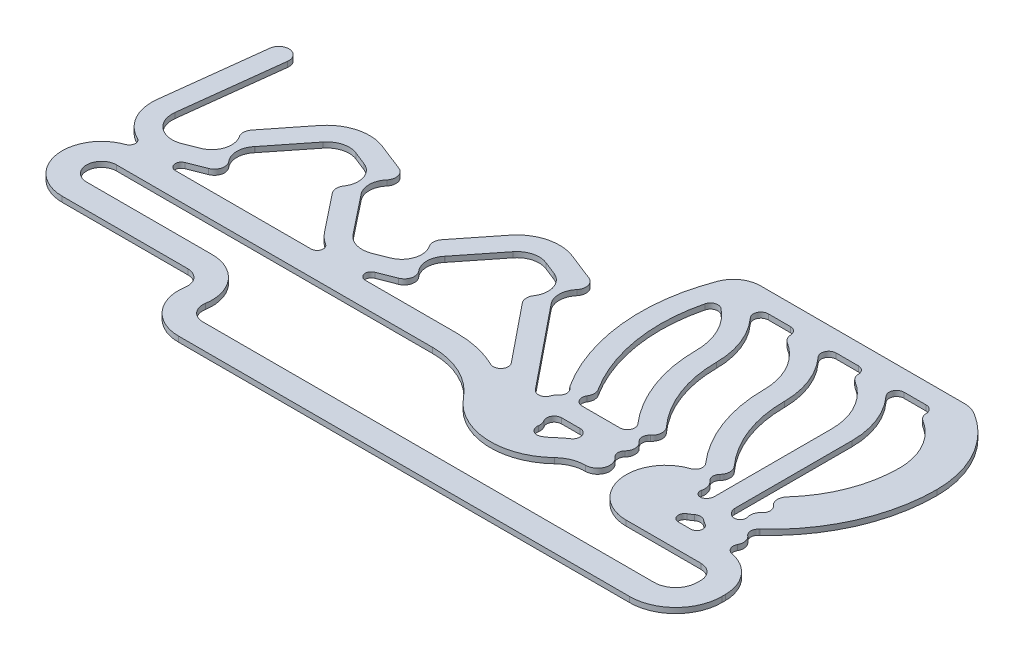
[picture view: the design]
SolidWorks part; units mm, degrees
other "<6021_lower_plate>-<Fillet8>"
ref_plane "X_Y" through (0, 0, 0) normal (0, 0, 1) x (1, 0, 0)
ref_plane "Z_X" through (0, 0, 0) normal (0, 1, 0) x (1, 0, 0)
ref_plane "Y_Z" through (0, 0, 0) normal (1, 0, 0) x (0, 0, -1)
ref_plane "X_Y-6021_lower_plate" through (0, 0, 0) normal (0, 0, 1) x (1, 0, 0)
ref_plane "Z_X-6021_lower_plate" through (0, 0, 0) normal (0, 1, 0) x (1, 0, 0)
ref_plane "Y_Z-6021_lower_plate" through (0, 0, 0) normal (1, 0, 0) x (0, 0, -1)
ref_plane "X_Y-_6021_master-6021_lower_plate" through (0, 0, 0) normal (0, 0, 1) x (1, 0, 0)
ref_plane "Z_X_peltier-_6021_master-6021_lower_plate" through (0, 0, 0) normal (0, 1, 0) x (1, 0, 0)
ref_plane "Y_Z-_6021_master-6021_lower_plate" through (0, 0, 0) normal (1, 0, 0) x (0, 0, -1)
sketch "zx_sketch-_6021_master-6021_lower_plate" plane through (0, 0, 0) normal (0, 1, 0) x (1, 0, 0)
  line L0 (0, 0) -> (0, 39833.2138) construction
  line L1 (-56.5, 24.66) -> (4, 24.66)
  line L2 (-56.5, 24.66) -> (-56.5, -27)
  line L3 (-56.5, -27) -> (56.5, -27)
  line L4 (56.5, 27) -> (56.5, -27)
  line L5 (0, 0) -> (39833.2138, 0) construction
  line L6 (4, 24.66) -> (4, 27)
  line L11 (4, 27) -> (56.5, 27)
  point P3 (0, -27)
  point P17 (-22.5, 15.66)
  point P18 (22.5, 15.66)
  point P19 (22.5, -15.66)
  point P20 (-22.5, -15.66)
  dimension "D1" = 113
  dimension "D2" = 24.66
  dimension "D3" = 45
  dimension "D4" = 31.32
  dimension "D5" = 27
  dimension "D6" = 2.34
  dimension "D7" = 4
  dimension "D8" = 27
sketch "xy_sketch-_6021_master-6021_lower_plate" plane through (0, 0, 0) normal (0, 0, 1) x (1, 0, 0)
  line L0 (0, 0) -> (0, 5) construction
  line L1 (0, 5) -> (0, 10) construction
  dimension "D1" = 5
  dimension "D2" = 5
ref_plane "zx_lower_plate-_6021_master-6021_lower_plate" through (0, 5, 0) normal (0, 1, 0) x (1, 0, 0)
ref_plane "zx_sensor-_6021_master-6021_lower_plate" through (0, 10, 0) normal (0, 1, 0) x (1, 0, 0)
sketch "zx_sensor_sketch-_6021_master-6021_lower_plate" plane through (0, 10, 0) normal (0, 1, 0) x (1, 0, 0)
  line L0 (-42.2, 3.16) -> (-28.2, 8.66) construction
  line L1 (-28.2, 8.66) -> (-14.2, 3.16) construction
  line L2 (-14.2, 3.16) -> (-0.2, 8.66) construction
  line L3 (-42.2, 4.96) -> (-42.2, -0.8) construction
  line L4 (-28.2, 10.46) -> (-28.2, 4.7) construction
  line L5 (-14.2, 4.96) -> (-14.2, -0.8) construction
  line L6 (-0.2, 10.46) -> (-0.2, 4.7) construction
  line L7 (-42.2, 3.16) -> (-42.2, -0.8) construction
  line L8 (-28.2, 8.66) -> (-28.2, 4.7) construction
  line L9 (-14.2, 3.16) -> (-14.2, -0.8) construction
  line L10 (-0.2, 8.66) -> (-0.2, 4.7) construction
  line L11 (-39.215, 3.16) -> (-45.185, 3.16) construction
  line L12 (-39.215, 7.475) -> (-39.215, -1.155) construction
  line L13 (-44.615, 3.16) -> (-39.785, 3.16) construction
  point P8 (-42.2, 2.08)
  point P16 (-42.2, 3.16)
  point P19 (-39.215, 3.16)
  point P22 (-42.2, 3.16)
  dimension "D1" = 42.2
  dimension "D2" = 3.16
  dimension "D3" = 14
  dimension "D4" = 1.08
  dimension "D5" = 3.96
  dimension "D6" = 5.76
  dimension "D7" = 5.97
  dimension "D8" = 0.8
  dimension "D9" = 8.63
  dimension "D10" = 4.83
  dimension "D11" = 5.5
sketch "zx_valve_sketch-_6021_master-6021_lower_plate" plane through (0, 10.9, 0) normal (0, 1, 0) x (1, 0, 0)
  line L0 (44, -4.25) -> (34, -4.25) construction
  line L1 (34, -4.25) -> (24, -4.25) construction
  line L2 (24, -4.25) -> (14, -4.25) construction
  line L3 (44, -10.5) -> (44, -6.5) construction
  line L4 (44, -6.5) -> (44, -2.5) construction
  line L5 (34, -2.5) -> (34, -6.5) construction
  line L6 (34, -6.5) -> (34, -10.5) construction
  line L7 (24, -2.5) -> (24, -6.5) construction
  line L8 (24, -6.5) -> (24, -10.5) construction
  line L9 (14, -2.5) -> (14, -6.5) construction
  line L10 (14, -6.5) -> (14, -10.5) construction
  line L11 (44, 10.5) -> (44, -19) construction
  line L12 (34, 10.5) -> (34, -19) construction
  line L14 (24, -19) -> (24, 10.5) construction
  line L17 (14, 10.5) -> (14, -19) construction
  point P20 (44, -4.25)
  dimension "D1" = 10
  dimension "D2" = 44
  dimension "D3" = 4.25
  dimension "D4" = 8
  dimension "D5" = 2.25
  dimension "D6" = 29.5
  dimension "D7" = 14.2
  dimension "D8" = 10.5
  dimension "D9" = 29.32
sketch "zx_manifold_sketch-_6021_master-6021_lower_plate" plane through (0, 5, 0) normal (0, 1, 0) x (1, 0, 0)
  line L0 (-34.0003, 7.58) -> (-22.3997, 7.58) construction
  line L4 (44, 19.5) -> (34, 19.5) construction
  line L5 (34, 19.5) -> (24, 19.5) construction
  line L6 (24, 19.5) -> (14, 19.5) construction
  line L7 (39, 10.5) -> (39, -7.6132)
  line L9 (-48.0003, 2.08) -> (-36.3997, 2.08) construction
  line L11 (-20.0003, 2.08) -> (-8.3997, 2.08) construction
  line L12 (-6.0003, 7.58) -> (5.6003, 7.58) construction
  line L13 (-48.9, -6.72) -> (-2.2958, -6.72)
  line L15 (14, -6.5) -> (24, -6.5)
  line L17 (-14.2, 4.96) -> (-9.7626, 10.5608)
  line L22 (34, -4.7265) -> (44, -4.7265) construction
  line L23 (44, -4.7265) -> (39, -7.6132) construction
  line L24 (-4.2467, 12.0482) -> (-0.2, 10.46)
  line L26 (44, 22) -> (14, 22)
  line L28 (-48.9, -14.72) -> (-30.3969, -14.72)
  line L30 (10.8896, -9.015) -> (7.7791, -11.53) construction
  line L31 (34, -14.5) -> (45, -14.5)
  line L32 (-22.5, -24) -> (44, -24)
  line L35 (-14.2, -0.8) -> (-18.2467, -2.3882)
  line L38 (-52.7667, 2.6469) -> (-51, 17.5)
  line L39 (-28.2, 4.7) -> (-23.7626, -0.9008)
  line L40 (14, 10.5) -> (22.5, 15.66) construction
  line L43 (49, -19) -> (49, -18.5)
  line L45 (-32.2467, 12.0482) -> (-28.2, 10.46)
  line L46 (-37.7626, 10.5608) -> (-42.2, 4.96)
  line L47 (-42.2, -0.8) -> (-46.2467, -2.3882)
  line L48 (-0.2, 4.7) -> (10.8896, -9.015)
  circle A0 centre (34, 19.5) radius 3.85 construction
  circle A1 centre (44, 19.5) radius 3.85 construction
  circle A2 centre (24, 19.5) radius 3.85 construction
  circle A3 centre (14, 19.5) radius 3.85 construction
  arc A4 (34, -10.5) -> (39, -7.6132) centre (34, -4.7265) ccw
  arc A6 (29, 10.5) -> (34, -2.5) centre (48.4, 10.5) ccw
  arc A7 (44, -10.5) -> (39, -7.6132) centre (44, -4.7265) cw
  arc A8 (44, -2.5) -> (49, 10.5) centre (29.6, 10.5) ccw
  arc A11 (45.3208, 21.6226) -> (44, 22) centre (44, 19.5) ccw
  arc A12 (44, -6.5) -> (51.5, 10.5) centre (28.4833, 10.5) ccw
  arc A13 (14, 22) -> (11.6636, 20.3896) centre (14, 19.5) ccw
  arc A15 (34, -14.5) -> (34, -6.5) centre (34, -10.5) cw
  arc A16 (-48.9, -6.72) -> (-48.9, -14.72) centre (-48.9, -10.72) ccw
  arc A17 (44, -24) -> (49, -19) centre (44, -19) ccw
  arc A18 (-22.5, -24) -> (-26.4485, -19.36) centre (-22.5, -20) cw
  arc A19 (-30.3969, -14.72) -> (-26.4485, -19.36) centre (-30.3969, -18.72) cw
  arc A20 (14, -10.5) -> (10.8896, -9.015) centre (14, -6.5) cw
  arc A21 (-4.2467, 12.0482) -> (-9.7626, 10.5608) centre (-6.0003, 7.58) ccw
  circle A22 centre (-51, 17.5) radius 3.85 construction
  arc A23 (-23.7626, -0.9008) -> (-18.2467, -2.3882) centre (-20.0003, 2.08) ccw
  arc A24 (-32.2467, 12.0482) -> (-37.7626, 10.5608) centre (-34.0003, 7.58) ccw
  arc A25 (-46.2467, -2.3882) -> (-52.7667, 2.6469) centre (-48.0003, 2.08) cw
  arc A26 (49, -18.5) -> (45, -14.5) centre (45, -18.5) ccw
  circle A27 centre (-51, 17.5) radius 5.5 construction
  arc A29 (14, 19.5) -> (19, 10.5) centre (8.4, 10.5) cw
  arc A30 (39, 10.5) -> (34, 19.5) centre (28.4, 10.5) ccw
  arc A31 (49, 10.5) -> (44, 19.5) centre (38.4, 10.5) ccw
  arc A32 (29, 10.5) -> (24, 19.5) centre (18.4, 10.5) ccw
  arc A33 (19, 10.5) -> (24, -2.5) centre (38.4, 10.5) ccw
  arc A35 (45.3208, 21.6226) -> (51.5, 10.5) centre (38.4, 10.5) cw
  arc A36 (14, -2.5) -> (11.6636, 20.3896) centre (35.6147, 11.2703) cw
  arc A37 (19.5172, -12.2931) -> (7.7791, -11.53) centre (14, -6.5) cw
  arc A38 (7.7791, -11.53) -> (-2.2958, -6.72) centre (-2.2958, -19.6763) ccw
  arc A39 (24, -10.5) -> (19.5172, -12.2931) centre (24, -17) ccw
  point P121 (-42.2, 2.08)
  dimension "D1" = 45.993
  dimension "D2" = 7.2783
  dimension "D4" = 85.419
  dimension "D5" = 58.011
  dimension "D6" = 92.9
  dimension "D7" = 34.592
  dimension "D8" = 47.712
  dimension "D9" = 60.268
  dimension "D10" = 5
  dimension "D13" = 34.946
  dimension "D14" = 17.5
  dimension "D15" = 15.65
  dimension "D16" = 70.41
  dimension "D17" = 173.817
  dimension "D19" = 30.895
  dimension "D21" = 0.7861
  dimension "D18" = 47.65
  dimension "D11" = 26.15
  dimension "D3" = 9
  dimension "D12" = 3
  dimension "D20" = 3.485
sketch "zx_screws_sketch-_6021_master-6021_lower_plate" plane through (0, 5, 0) normal (0, 1, 0) x (1, 0, 0)
  line L4 (-34.0003, 7.58) -> (-22.3997, 7.58) construction
  line L5 (-20.0003, 2.08) -> (-8.3997, 2.08) construction
  line L6 (-6.0003, 7.58) -> (5.6003, 7.58) construction
  line L7 (-36.3997, 2.08) -> (-48.0003, 2.08) construction
  line L13 (56.5, 27) -> (56.5, -27) construction
  circle A0 centre (52.5, 23) radius 4 construction
  circle A3 centre (52.5, -23) radius 4 construction
  arc A7 (-52.7667, 2.6469) -> (-46.2467, -2.3882) centre (-48.0003, 2.08) ccw construction
  circle A8 centre (-52.5, -23) radius 4 construction
  point P0 (-0.2, -19)
  point P1 (52.5, -23)
  point P2 (52.5, 23)
  point P3 (6.6, 23)
  point P4 (-52.5, -23)
  point P5 (-42.2, 17.5)
  dimension "D3" = 5.743
  dimension "D4" = 4.3941
  dimension "D11" = 7.7312
  dimension "D1" = 44.8364
  dimension "D2" = 4
  dimension "D5" = 3.6997
  dimension "D6" = 15
  dimension "D7" = 6.6
  dimension "D8" = 52.5
  dimension "D9" = 57.717
  dimension "D10" = 4
ref_plane "yz_sensor-_6021_master-6021_lower_plate" through (-42.2, 0, 0) normal (1, 0, 0) x (0, 0, -1)
ref_plane "zx_valve-_6021_master-6021_lower_plate" through (0, 10.9, 0) normal (0, 1, 0) x (1, 0, 0)
ref_plane "zx_sensor_shelf-_6021_master-6021_lower_plate" through (0, 12.391, 0) normal (0, 1, 0) x (1, 0, 0)
sketch "Sketch7-6021_lower_plate" plane through (0, 5, 0) normal (0, 1, 0) x (1, 0, 0)
  line L6 (-56.5, -27) -> (56.5, -27)
  line L7 (56.5, 27) -> (56.5, -27)
  line L8 (4, 27) -> (56.5, 27)
  line L9 (4, 24.66) -> (4, 27)
  line L10 (-56.5, 24.66) -> (4, 24.66)
  line L11 (-56.5, 24.66) -> (-56.5, -27)
sketch "Sketch33-6021_lower_plate" plane through (0, 5, 0) normal (0, 1, 0) x (1, 0, 0)
  line L6 (-50.6814, 2.3989) -> (-48.9147, 17.252)
  line L7 (-42.9672, 1.1548) -> (-47.0139, -0.4334)
  line L10 (-54.852, 2.895) -> (-53.0853, 17.748)
  line L11 (-41.4328, -2.7548) -> (-45.4795, -4.343)
  line L15 (44, 24.1) -> (14, 24.1)
  line L19 (44, 19.9) -> (14, 19.9)
  line L23 (-40.554, 3.6559) -> (-36.1166, 9.2567)
  line L24 (-33.0139, 10.0934) -> (-28.9672, 8.5052)
  line L27 (-43.846, 6.2641) -> (-39.4086, 11.8649)
  line L28 (-31.4795, 14.003) -> (-27.4328, 12.4148)
  line L33 (-17.4795, -4.343) -> (-13.4328, -2.7548)
  line L34 (-29.846, 3.3959) -> (-25.4086, -2.2049)
  line L37 (-19.0139, -0.4334) -> (-14.9672, 1.1548)
  line L38 (-26.554, 6.0041) -> (-22.1166, 0.4033)
  line L40 (-1.833, 3.3796) -> (9.2566, -10.3354)
  line L43 (-5.0139, 10.0934) -> (-0.9672, 8.5052)
  line L44 (-12.554, 3.6559) -> (-8.1166, 9.2567)
  line L47 (-3.4795, 14.003) -> (0.5672, 12.4148)
  line L48 (-15.846, 6.2641) -> (-11.4086, 11.8649)
  line L50 (1.433, 6.0204) -> (12.5225, -7.6946)
  arc A0 (-53.0853, 17.748) -> (-48.9147, 17.252) centre (-51, 17.5) cw
  arc A1 (-42.9672, 1.1548) -> (-41.4328, -2.7548) centre (-42.2, -0.8) cw
  arc A3 (-50.6814, 2.3989) -> (-47.0139, -0.4334) centre (-48.0003, 2.08) ccw
  arc A5 (-54.852, 2.895) -> (-45.4795, -4.343) centre (-48.0003, 2.08) ccw
  arc A9 (-1.833, 3.3796) -> (1.433, 6.0204) centre (-0.2, 4.7) cw
  arc A14 (-33.0139, 10.0934) -> (-36.1166, 9.2567) centre (-34.0003, 7.58) ccw
  arc A16 (-31.4795, 14.003) -> (-39.4086, 11.8649) centre (-34.0003, 7.58) ccw
  arc A32 (12.2289, -3.6283) -> (15.7711, -1.3717) centre (14, -2.5) ccw
  arc A33 (14, -8.4) -> (14, -12.6) centre (14, -10.5) cw
  arc A34 (42.5843, -4.949) -> (45.4157, -8.051) centre (44, -6.5) ccw
  arc A43 (-25.4086, -2.2049) -> (-17.4795, -4.343) centre (-20.0003, 2.08) ccw
  arc A45 (-22.1166, 0.4033) -> (-19.0139, -0.4334) centre (-20.0003, 2.08) ccw
  arc A48 (-5.0139, 10.0934) -> (-8.1166, 9.2567) centre (-6.0003, 7.58) ccw
  arc A50 (-3.4795, 14.003) -> (-11.4086, 11.8649) centre (-6.0003, 7.58) ccw
  arc A51 (-43.846, 6.2641) -> (-40.554, 3.6559) centre (-42.2, 4.96) ccw
  arc A56 (-28.9672, 8.5052) -> (-27.4328, 12.4148) centre (-28.2, 10.46) ccw
  arc A57 (-29.846, 3.3959) -> (-26.554, 6.0041) centre (-28.2, 4.7) cw
  arc A58 (-15.846, 6.2641) -> (-12.554, 3.6559) centre (-14.2, 4.96) ccw
  arc A59 (-14.9672, 1.1548) -> (-13.4328, -2.7548) centre (-14.2, -0.8) cw
  arc A60 (0.5672, 12.4148) -> (-0.9672, 8.5052) centre (-0.2, 10.46) cw
  arc A67 (9.7011, 21.1368) -> (12.2289, -3.6283) centre (35.6147, 11.2703) ccw
  arc A69 (9.2566, -10.3354) -> (14, -12.6) centre (14, -6.5) ccw
  arc A71 (12.5225, -7.6946) -> (14, -8.4) centre (14, -6.5) ccw
  arc A72 (14, 24.1) -> (9.7011, 21.1368) centre (14, 19.5) ccw
  arc A73 (46.4302, 23.4057) -> (44, 24.1) centre (44, 19.5) ccw
  arc A74 (53.6, 10.5) -> (46.4302, 23.4057) centre (38.4, 10.5) ccw
  arc A75 (45.4157, -8.051) -> (53.6, 10.5) centre (28.4833, 10.5) ccw
  arc A81 (13.6262, 19.6423) -> (15.7711, -1.3717) centre (35.6147, 11.2703) ccw
  arc A82 (14, 19.9) -> (13.6262, 19.6423) centre (14, 19.5) ccw
  arc A83 (44.2113, 19.8396) -> (44, 19.9) centre (44, 19.5) ccw
  arc A84 (49.4, 10.5) -> (44.2113, 19.8396) centre (38.4, 10.5) ccw
  arc A85 (42.5843, -4.949) -> (49.4, 10.5) centre (28.4833, 10.5) ccw
  dimension "D5" = 2.1
  dimension "D13" = 2.1
  dimension "D11" = 2.1
  dimension "D3" = 2.1
  dimension "D1" = 2.1
  dimension "D2" = 2.1
  dimension "D4" = 2.1
  dimension "D6" = 2.1
  dimension "D7" = 2.1
  dimension "D8" = 2.1
  dimension "D9" = 2.1
  dimension "D10" = 2.1
  dimension "D12" = 2.1
  dimension "D14" = 2.1
sketch "Sketch34-6021_lower_plate" plane through (0, 5, 0) normal (0, 1, 0) x (1, 0, 0)
  line L5 (41.1, -6.9814) -> (41.1, 10.5)
  line L7 (36.9, -6.9814) -> (36.9, 10.5)
  line L10 (14, -8.6) -> (24, -8.6)
  line L12 (14, -4.4) -> (24, -4.4)
  arc A5 (14, -4.4) -> (14, -8.6) centre (14, -6.5) ccw
  arc A11 (31.1, 10.5) -> (35.5588, -1.0928) centre (48.4, 10.5) ccw
  arc A12 (31.1, 10.5) -> (25.1094, 21.283) centre (18.4, 10.5) ccw
  arc A15 (26.9, 10.5) -> (32.4412, -3.9072) centre (48.4, 10.5) ccw
  arc A16 (26.9, 10.5) -> (22.8906, 17.717) centre (18.4, 10.5) ccw
  arc A18 (41.1, -6.9814) -> (44, -8.4) centre (44, -4.7265) ccw
  arc A19 (41.1, 10.5) -> (35.1094, 21.283) centre (28.4, 10.5) ccw
  arc A22 (39, -10.8086) -> (44, -12.6) centre (44, -4.7265) ccw
  arc A23 (36.9, 10.5) -> (32.8906, 17.717) centre (28.4, 10.5) ccw
  arc A25 (34, -12.6) -> (39, -10.8086) centre (34, -4.7265) ccw
  arc A27 (34, -8.4) -> (36.9, -6.9814) centre (34, -4.7265) ccw
  arc A28 (24, -4.4) -> (24, -8.6) centre (24, -6.5) cw
  arc A29 (35.5588, -1.0928) -> (32.4412, -3.9072) centre (34, -2.5) cw
  arc A30 (34, -8.4) -> (34, -12.6) centre (34, -10.5) ccw
  arc A31 (44, -8.4) -> (44, -12.6) centre (44, -10.5) cw
  arc A32 (22.8906, 17.717) -> (25.1094, 21.283) centre (24, 19.5) cw
  arc A33 (35.1094, 21.283) -> (32.8906, 17.717) centre (34, 19.5) ccw
  arc A36 (42.8906, 17.717) -> (45.1094, 21.283) centre (44, 19.5) cw
  arc A37 (45.5588, -3.9072) -> (42.4412, -1.0928) centre (44, -2.5) cw
  arc A40 (51.1, 10.5) -> (45.1094, 21.283) centre (38.4, 10.5) ccw
  arc A41 (45.5588, -3.9072) -> (51.1, 10.5) centre (29.6, 10.5) ccw
  arc A44 (46.9, 10.5) -> (42.8906, 17.717) centre (38.4, 10.5) ccw
  arc A45 (42.4412, -1.0928) -> (46.9, 10.5) centre (29.6, 10.5) ccw
  dimension "D9" = 2.1
  dimension "D11" = 2.1
  dimension "D1" = 2.1
  dimension "D2" = 2.1
  dimension "D3" = 2.1
  dimension "D4" = 2.1
  dimension "D5" = 2.1
  dimension "D6" = 2.1
  dimension "D7" = 2.1
  dimension "D8" = 2.1
  dimension "D10" = 2.1
sketch "Sketch35-6021_lower_plate" plane through (0, 5, 0) normal (0, 1, 0) x (1, 0, 0)
  line L45 (34, -16.9) -> (45, -16.9)
  line L46 (46.6, -18.5) -> (46.6, -19)
  line L47 (44, -21.6) -> (-22.5, -21.6)
  line L48 (-30.3969, -12.32) -> (-48.9, -12.32)
  line L49 (-48.9, -9.12) -> (-2.2958, -9.12)
  line L55 (34, -12.1) -> (45, -12.1)
  line L56 (51.4, -18.5) -> (51.4, -19)
  line L57 (44, -26.4) -> (-22.5, -26.4)
  line L58 (-30.3969, -17.12) -> (-48.9, -17.12)
  line L59 (-48.9, -4.32) -> (-2.2958, -4.32)
  arc A8 (12.8906, 17.717) -> (15.1094, 21.283) centre (14, 19.5) cw
  arc A9 (21.1, 10.5) -> (25.5588, -1.0928) centre (38.4, 10.5) ccw
  arc A11 (21.1, 10.5) -> (15.1094, 21.283) centre (8.4, 10.5) ccw
  arc A13 (22.4412, -3.9072) -> (25.5588, -1.0928) centre (24, -2.5) ccw
  arc A50 (16.9, 10.5) -> (22.4412, -3.9072) centre (38.4, 10.5) ccw
  arc A51 (16.9, 10.5) -> (12.8906, 17.717) centre (8.4, 10.5) ccw
  arc A69 (24, -8.1) -> (24, -12.9) centre (24, -10.5) cw
  arc A70 (34, -4.1) -> (34, -8.9) centre (34, -6.5) cw
  arc A71 (17.8621, -10.5552) -> (24, -8.1) centre (24, -17) cw
  arc A72 (21.1724, -14.031) -> (24, -12.9) centre (24, -17) cw
  arc A87 (34, -4.1) -> (34, -16.9) centre (34, -10.5) ccw
  arc A88 (46.6, -18.5) -> (45, -16.9) centre (45, -18.5) ccw
  arc A89 (44, -21.6) -> (46.6, -19) centre (44, -19) ccw
  arc A90 (-24.0794, -19.744) -> (-22.5, -21.6) centre (-22.5, -20) ccw
  arc A91 (-24.0794, -19.744) -> (-30.3969, -12.32) centre (-30.3969, -18.72) ccw
  arc A92 (-48.9, -9.12) -> (-48.9, -12.32) centre (-48.9, -10.72) ccw
  arc A93 (5.9129, -13.039) -> (-2.2958, -9.12) centre (-2.2958, -19.6763) ccw
  arc A94 (5.9129, -13.039) -> (21.1724, -14.031) centre (14, -6.5) ccw
  arc A119 (34, -8.9) -> (34, -12.1) centre (34, -10.5) ccw
  arc A120 (51.4, -18.5) -> (45, -12.1) centre (45, -18.5) ccw
  arc A121 (44, -26.4) -> (51.4, -19) centre (44, -19) ccw
  arc A122 (-28.8175, -18.976) -> (-22.5, -26.4) centre (-22.5, -20) ccw
  arc A123 (-28.8175, -18.976) -> (-30.3969, -17.12) centre (-30.3969, -18.72) ccw
  arc A124 (-48.9, -4.32) -> (-48.9, -17.12) centre (-48.9, -10.72) ccw
  arc A125 (9.6454, -10.021) -> (-2.2958, -4.32) centre (-2.2958, -19.6763) ccw
  arc A126 (9.6454, -10.021) -> (17.8621, -10.5552) centre (14, -6.5) ccw
  dimension "D5" = 2.1
  dimension "D1" = 2.4
  dimension "D2" = 2.4
  dimension "D3" = 2.1
  dimension "D4" = 2.1
  dimension "D6" = 2.1
sketch "Sketch36-6021_lower_plate" plane through (0, 5, 0) normal (0, 1, 0) x (1, 0, 0)
  line L1 (-42.9672, 1.1548) -> (-45.0438, 0.3399)
  line L3 (-31.0261, 9.3132) -> (-28.9672, 8.5052)
  arc A0 (-43.9508, 3.8004) -> (-45.0438, 0.3399) centre (-45.8963, 2.512) cw
  arc A2 (-40.6034, 3.5958) -> (-40.6034, 0.5642) centre (-38.8294, 2.08) ccw
  arc A5 (-40.6034, 0.5642) -> (-42.9672, 1.1548) centre (-42.2, -0.8) ccw
  arc A6 (-43.9508, 3.8004) -> (-40.6034, 3.5958) centre (-42.2, 4.96) ccw
  arc A9 (-26.6075, 6.0689) -> (-29.9458, 5.8671) centre (-28.2, 4.7) ccw
  arc A10 (-28.9672, 8.5052) -> (-26.6075, 9.0911) centre (-28.2, 10.46) ccw
  arc A11 (-26.6075, 9.0911) -> (-26.6075, 6.0689) centre (-24.8496, 7.58) ccw
  arc A12 (-31.0261, 9.3132) -> (-29.9458, 5.8671) centre (-31.873, 7.1554) cw
  dimension "D1" = 2.4
  dimension "D2" = 2.4
sketch "xz_cover-_6021_master-6021_lower_plate" plane through (0, 0, 0) normal (0, 1, 0) x (1, 0, 0)
  line L1 (-63, -36.79) -> (63, -36.79)
  line L2 (-71.85, -27.94) -> (-71.85, 30.02)
  line L3 (-71.85, 30.02) -> (71.85, 30.02)
  line L4 (71.85, -27.94) -> (71.85, 30.02)
  line L5 (-71.85, -36.79) -> (71.85, 30.02) construction
  line L6 (-71.85, 30.02) -> (71.85, -36.79) construction
  line L7 (0, -1003.385) -> (0, 48996.615) construction
  arc A0 (71.85, -27.94) -> (63, -36.79) centre (63, -27.94) cw
  arc A1 (-63, -36.79) -> (-71.85, -27.94) centre (-63, -27.94) cw
  circle A2 centre (-64.495, 5.21) radius 3.6
  circle A3 centre (64.495, 5.21) radius 3.6
  point P0 (0, -3.385)
  dimension "D4" = 8.85
  dimension "D5" = 42
  dimension "D7" = 7.2
  dimension "D1" = 66.81
  dimension "D2" = 143.7
  dimension "D3" = 36.79
  dimension "D6" = 128.99
  dimension "D8" = 0
inserted part "6021_lower_plate"
sketch "Sketch25" plane through (0, 4.4, 0) normal (0, 1, 0) x (1, 0, 0)
  line L1 (-52.4895, 17.6772) -> (-54.2562, 2.8241)
  line L7 (-2.2958, -8.52) -> (-48.9, -8.52)
  line L22 (37.5, -6.8028) -> (37.5, 10.5)
  line L26 (40.5, 10.5) -> (40.5, -6.8028)
  line L30 (5.4905, -4.7233) -> (-1.3664, 3.7569)
  line L64 (40.5, 10.5) -> (40.5, -6.8028)
  line L67 (38.0953, -12.7) -> (39.9047, -12.7)
  line L68 (16.1909, -5) -> (21.7675, -5)
  line L73 (37.5, -6.8028) -> (37.5, 10.5)
  line L115 (-2.2958, -8.52) -> (-48.9, -8.52)
  line L141 (41.4019, 20.5) -> (38.1483, 20.5)
  line L161 (38.0953, -12.7) -> (39.9047, -12.7)
  line L167 (31.4019, 20.5) -> (28.1483, 20.5)
  line L171 (31.4019, 20.5) -> (28.1483, 20.5)
  line L179 (-48.9, -12.92) -> (-30.3969, -12.92)
  line L191 (-48.9, -12.92) -> (-30.3969, -12.92)
  line L204 (-22.5, -22.2) -> (44, -22.2)
  line L210 (41.4019, 20.5) -> (38.1483, 20.5)
  line L226 (16.1909, -5) -> (21.7675, -5)
  line L228 (18.9059, -8) -> (16.1909, -8)
  line L230 (18.9059, -8) -> (16.1909, -8)
  line L234 (-41.652, -2.1963) -> (-44.164, -3.1822)
  line L236 (-43.8352, -4.92) -> (-23.8252, -4.92)
  line L238 (-24.9383, -1.8323) -> (-29.3757, 3.7685)
  line L240 (-30.8069, 9.8717) -> (-32.7947, 10.6519)
  line L242 (-36.5869, 9.6293) -> (-41.0243, 4.0285)
  line L244 (-41.652, -2.1963) -> (-44.164, -3.1822)
  line L245 (-43.8352, -4.92) -> (-23.8252, -4.92)
  line L246 (-24.9383, -1.8323) -> (-29.3757, 3.7685)
  line L247 (-30.8069, 9.8717) -> (-32.7947, 10.6519)
  line L248 (-36.5869, 9.6293) -> (-41.0243, 4.0285)
  line L289 (5.4905, -4.7233) -> (-1.3664, 3.7569)
  line L291 (-2.8069, 9.8717) -> (-4.7947, 10.6519)
  line L293 (-2.8069, 9.8717) -> (-4.7947, 10.6519)
  line L295 (-8.5869, 9.6293) -> (-13.0243, 4.0285)
  line L297 (-52.4895, 17.6772) -> (-54.2562, 2.8241)
  line L298 (-51.2772, 2.4698) -> (-49.5105, 17.3228)
  line L299 (-51.2772, 2.4698) -> (-49.5105, 17.3228)
  line L300 (-44.8246, -0.2187) -> (-46.7947, -0.9919)
  line L301 (-44.8246, -0.2187) -> (-46.7947, -0.9919)
  line L302 (-38.9383, 11.4923) -> (-43.3757, 5.8915)
  line L303 (-38.9383, 11.4923) -> (-43.3757, 5.8915)
  line L304 (-27.652, 11.8563) -> (-31.6987, 13.4445)
  line L305 (-27.652, 11.8563) -> (-31.6987, 13.4445)
  line L306 (-22.5869, 0.0307) -> (-27.0243, 5.6315)
  line L307 (-22.5869, 0.0307) -> (-27.0243, 5.6315)
  line L308 (-16.8246, -0.2187) -> (-18.7947, -0.9919)
  line L309 (-16.8246, -0.2187) -> (-18.7947, -0.9919)
  line L310 (-10.9383, 11.4923) -> (-15.3757, 5.8915)
  line L311 (-10.9383, 11.4923) -> (-15.3757, 5.8915)
  line L312 (0.348, 11.8563) -> (-3.6987, 13.4445)
  line L313 (0.348, 11.8563) -> (-3.6987, 13.4445)
  line L314 (10.6785, -6.3682) -> (0.9664, 5.6431)
  line L315 (10.6785, -6.3682) -> (0.9664, 5.6431)
  line L316 (44, 23.5) -> (14, 23.5)
  line L317 (44, 23.5) -> (14, 23.5)
  line L318 (50.8, -19) -> (50.8, -18.5)
  line L319 (50.8, -19) -> (50.8, -18.5)
  line L320 (-22.5, -25.8) -> (44, -25.8)
  line L321 (-22.5, -25.8) -> (44, -25.8)
  line L322 (-48.9, -16.52) -> (-30.3969, -16.52)
  line L323 (-48.9, -16.52) -> (-30.3969, -16.52)
  line L324 (-8.5869, 9.6293) -> (-13.0243, 4.0285)
  line L325 (-13.652, -2.1963) -> (-16.164, -3.1822)
  line L326 (-13.652, -2.1963) -> (-16.164, -3.1822)
  line L327 (-15.8352, -4.92) -> (-2.2958, -4.92)
  line L328 (-15.8352, -4.92) -> (-2.2958, -4.92)
  line L330 (-22.5, -22.2) -> (44, -22.2)
  line L331 (47.2, -19) -> (47.2, -18.5)
  line L332 (47.2, -19) -> (47.2, -18.5)
  line L333 (45, -16.3) -> (34, -16.3)
  line L334 (45, -16.3) -> (34, -16.3)
  line L335 (21.4019, 20.5) -> (18.1483, 20.5)
  line L336 (21.4019, 20.5) -> (18.1483, 20.5)
  arc A5 (39.6568, -10.5609) -> (40.3556, -11.0211) centre (44, -4.7265) ccw
  arc A6 (27.5, 10.5) -> (32.6445, -3.2323) centre (48.4, 10.5) ccw
  arc A7 (45.3238, -11.2053) -> (44.9585, -9.3462) centre (44, -10.5) ccw
  arc A12 (-4.7947, 10.6519) -> (-8.5869, 9.6293) centre (-6.0003, 7.58) ccw
  arc A35 (45.3238, -11.2053) -> (44.9585, -9.3462) centre (44, -10.5) ccw
  arc A64 (37.1098, -7.6577) -> (37.2319, -7.5225) centre (34, -4.7265) ccw
  arc A72 (37.1098, -7.6577) -> (37.2319, -7.5225) centre (34, -4.7265) ccw
  arc A76 (40.7681, -7.5225) -> (41.0911, -7.8571) centre (44, -4.7265) ccw
  arc A84 (40.7681, -7.5225) -> (41.0911, -7.8571) centre (44, -4.7265) ccw
  arc A175 (-1.447, 5.5336) -> (-2.8069, 9.8717) centre (-3.873, 7.1554) ccw
  arc A191 (-1.447, 5.5336) -> (-2.8069, 9.8717) centre (-3.873, 7.1554) ccw
  arc A302 (37.2319, -7.5225) -> (37.5, -6.8028) centre (36.4, -6.8028) ccw
  arc A326 (42.8866, -1.4948) -> (43.0401, -3.6527) centre (44, -2.5) ccw
  arc A374 (37.2319, -7.5225) -> (37.5, -6.8028) centre (36.4, -6.8028) ccw
  arc A415 (-4.7947, 10.6519) -> (-8.5869, 9.6293) centre (-6.0003, 7.58) ccw
  arc A460 (27.5, 10.5) -> (32.6445, -3.2323) centre (48.4, 10.5) ccw
  arc A508 (37.5, 10.5) -> (33.2075, 18.2264) centre (28.4, 10.5) ccw
  arc A512 (37.5, 10.5) -> (33.2075, 18.2264) centre (28.4, 10.5) ccw
  arc A516 (42.8866, -1.4948) -> (43.0401, -3.6527) centre (44, -2.5) ccw
  arc A521 (42.8866, -1.4948) -> (47.5, 10.5) centre (29.6, 10.5) ccw
  arc A532 (42.8866, -1.4948) -> (47.5, 10.5) centre (29.6, 10.5) ccw
  arc A538 (39.6568, -10.5609) -> (40.3556, -11.0211) centre (44, -4.7265) ccw
  arc A548 (39.6568, -10.5609) -> (38.3432, -10.5609) centre (39, -11.4433) ccw
  arc A552 (39.6568, -10.5609) -> (38.3432, -10.5609) centre (39, -11.4433) ccw
  arc A556 (37.6444, -11.0211) -> (38.3432, -10.5609) centre (34, -4.7265) ccw
  arc A561 (37.6444, -11.0211) -> (38.3432, -10.5609) centre (34, -4.7265) ccw
  arc A566 (-54.2562, 2.8241) -> (-50.7411, -3.5926) centre (-48.0003, 2.08) ccw
  arc A574 (27.5, 10.5) -> (23.2075, 18.2264) centre (18.4, 10.5) ccw
  arc A576 (-13.0596, 3.9856) -> (-13.0243, 4.0285) centre (-14.2, 4.96) ccw
  arc A578 (32.5011, 19.4423) -> (33.2075, 18.2264) centre (34, 19.5) ccw
  arc A585 (32.5011, 19.4423) -> (33.2075, 18.2264) centre (34, 19.5) ccw
  arc A588 (-13.0596, 3.9856) -> (-13.0243, 4.0285) centre (-14.2, 4.96) ccw
  arc A592 (-13.0596, 3.9856) -> (-13.0596, 0.1744) centre (-10.8294, 2.08) ccw
  arc A596 (-13.0596, 3.9856) -> (-13.0596, 0.1744) centre (-10.8294, 2.08) ccw
  arc A605 (-13.652, -2.1963) -> (-13.0596, 0.1744) centre (-14.2, -0.8) ccw
  arc A611 (27.5, 10.5) -> (23.2075, 18.2264) centre (18.4, 10.5) ccw
  arc A615 (22.5011, 19.4423) -> (23.2075, 18.2264) centre (24, 19.5) ccw
  arc A619 (22.5011, 19.4423) -> (23.2075, 18.2264) centre (24, 19.5) ccw
  arc A641 (19.502, -10.0245) -> (18.2759, -10.9897) centre (24, -17) ccw
  arc A643 (15.264, -3.3077) -> (15.2651, -1.694) centre (14, -2.5) ccw
  arc A645 (30.5, 10.5) -> (27.336, 18.6583) centre (18.4, 10.5) ccw
  arc A647 (30.5, 10.5) -> (27.336, 18.6583) centre (18.4, 10.5) ccw
  arc A649 (30.5, 10.5) -> (35.1134, -1.4948) centre (48.4, 10.5) ccw
  arc A651 (30.5, 10.5) -> (35.1134, -1.4948) centre (48.4, 10.5) ccw
  arc A653 (47.5, 10.5) -> (43.2075, 18.2264) centre (38.4, 10.5) ccw
  arc A655 (47.5, 10.5) -> (43.2075, 18.2264) centre (38.4, 10.5) ccw
  arc A657 (42.5011, 19.4423) -> (43.2075, 18.2264) centre (44, 19.5) ccw
  arc A659 (42.5011, 19.4423) -> (43.2075, 18.2264) centre (44, 19.5) ccw
  arc A661 (40.5, 10.5) -> (37.336, 18.6583) centre (28.4, 10.5) ccw
  arc A663 (40.5, 10.5) -> (37.336, 18.6583) centre (28.4, 10.5) ccw
  arc A665 (39.9047, -12.7) -> (40.3556, -11.0211) centre (39.9047, -11.8) ccw
  arc A667 (39.9047, -12.7) -> (40.3556, -11.0211) centre (39.9047, -11.8) ccw
  arc A669 (37.6444, -11.0211) -> (38.0953, -12.7) centre (38.0953, -11.8) ccw
  arc A671 (37.6444, -11.0211) -> (38.0953, -12.7) centre (38.0953, -11.8) ccw
  arc A682 (15.264, -3.3077) -> (16.1909, -5) centre (16.1909, -3.9) ccw
  arc A685 (-13.652, -2.1963) -> (-13.0596, 0.1744) centre (-14.2, -0.8) ccw
  arc A687 (-16.164, -3.1822) -> (-15.8352, -4.92) centre (-15.8352, -4.02) ccw
  arc A691 (4.1543, -6.4043) -> (-2.2958, -4.92) centre (-2.2958, -19.6763) ccw
  arc A693 (4.1543, -6.4043) -> (-2.2958, -4.92) centre (-2.2958, -19.6763) ccw
  arc A695 (4.1543, -6.4043) -> (5.4905, -4.7233) centre (4.6351, -5.415) ccw
  arc A697 (4.1543, -6.4043) -> (5.4905, -4.7233) centre (4.6351, -5.415) ccw
  arc A699 (-1.447, 5.5336) -> (-1.3664, 3.7569) centre (-0.2, 4.7) ccw
  arc A701 (-1.447, 5.5336) -> (-1.3664, 3.7569) centre (-0.2, 4.7) ccw
  arc A703 (21.7675, -5) -> (22.5991, -3.18) centre (21.7675, -3.9) ccw
  arc A709 (-54.2562, 2.8241) -> (-50.7411, -3.5926) centre (-48.0003, 2.08) ccw
  arc A710 (-49.5105, 17.3228) -> (-52.4895, 17.6772) centre (-51, 17.5) ccw
  arc A711 (-49.5105, 17.3228) -> (-52.4895, 17.6772) centre (-51, 17.5) ccw
  arc A712 (-51.2772, 2.4698) -> (-46.7947, -0.9919) centre (-48.0003, 2.08) ccw
  arc A713 (-51.2772, 2.4698) -> (-46.7947, -0.9919) centre (-48.0003, 2.08) ccw
  arc A714 (-44.8246, -0.2187) -> (-43.4506, 4.1317) centre (-45.8963, 2.512) ccw
  arc A715 (-44.8246, -0.2187) -> (-43.4506, 4.1317) centre (-45.8963, 2.512) ccw
  arc A716 (-43.3757, 5.8915) -> (-43.4506, 4.1317) centre (-42.2, 4.96) ccw
  arc A717 (-43.3757, 5.8915) -> (-43.4506, 4.1317) centre (-42.2, 4.96) ccw
  arc A718 (-31.6987, 13.4445) -> (-38.9383, 11.4923) centre (-34.0003, 7.58) ccw
  arc A719 (-31.6987, 13.4445) -> (-38.9383, 11.4923) centre (-34.0003, 7.58) ccw
  arc A720 (-27.0625, 9.4822) -> (-27.652, 11.8563) centre (-28.2, 10.46) ccw
  arc A721 (-27.0625, 9.4822) -> (-27.652, 11.8563) centre (-28.2, 10.46) ccw
  arc A722 (-27.0625, 9.4822) -> (-27.0625, 5.6778) centre (-24.8496, 7.58) ccw
  arc A723 (-27.0625, 9.4822) -> (-27.0625, 5.6778) centre (-24.8496, 7.58) ccw
  arc A724 (-27.0243, 5.6315) -> (-27.0625, 5.6778) centre (-28.2, 4.7) ccw
  arc A725 (-27.0243, 5.6315) -> (-27.0625, 5.6778) centre (-28.2, 4.7) ccw
  arc A726 (-22.5869, 0.0307) -> (-18.7947, -0.9919) centre (-20.0003, 2.08) ccw
  arc A727 (-22.5869, 0.0307) -> (-18.7947, -0.9919) centre (-20.0003, 2.08) ccw
  arc A728 (-16.8246, -0.2187) -> (-15.4506, 4.1317) centre (-17.8963, 2.512) ccw
  arc A729 (-16.8246, -0.2187) -> (-15.4506, 4.1317) centre (-17.8963, 2.512) ccw
  arc A730 (-15.3757, 5.8915) -> (-15.4506, 4.1317) centre (-14.2, 4.96) ccw
  arc A731 (-15.3757, 5.8915) -> (-15.4506, 4.1317) centre (-14.2, 4.96) ccw
  arc A732 (-3.6987, 13.4445) -> (-10.9383, 11.4923) centre (-6.0003, 7.58) ccw
  arc A733 (-3.6987, 13.4445) -> (-10.9383, 11.4923) centre (-6.0003, 7.58) ccw
  arc A734 (0.9375, 9.4822) -> (0.348, 11.8563) centre (-0.2, 10.46) ccw
  arc A735 (0.9375, 9.4822) -> (0.348, 11.8563) centre (-0.2, 10.46) ccw
  arc A736 (0.9375, 9.4822) -> (0.9375, 5.6778) centre (3.1504, 7.58) ccw
  arc A737 (0.9375, 9.4822) -> (0.9375, 5.6778) centre (3.1504, 7.58) ccw
  arc A738 (13.0415, -5.3462) -> (12.5772, -6.025) centre (14, -6.5) ccw
  arc A739 (13.0415, -5.3462) -> (12.5772, -6.025) centre (14, -6.5) ccw
  arc A740 (-50.8327, -5.2515) -> (-48.9, -16.52) centre (-48.9, -10.72) ccw
  arc A741 (-50.8327, -5.2515) -> (-48.9, -16.52) centre (-48.9, -10.72) ccw
  arc A742 (-50.8327, -5.2515) -> (-50.7411, -3.5926) centre (-51.1326, -4.4029) ccw
  arc A743 (-50.8327, -5.2515) -> (-50.7411, -3.5926) centre (-51.1326, -4.4029) ccw
  arc A744 (0.9664, 5.6431) -> (0.9375, 5.6778) centre (-0.2, 4.7) ccw
  arc A745 (0.9664, 5.6431) -> (0.9375, 5.6778) centre (-0.2, 4.7) ccw
  arc A746 (10.6785, -6.3682) -> (12.5772, -6.025) centre (11.5338, -5.6766) ccw
  arc A747 (10.6785, -6.3682) -> (12.5772, -6.025) centre (11.5338, -5.6766) ccw
  arc A748 (13.0415, -5.3462) -> (13.0415, -3.6538) centre (12.3387, -4.5) ccw
  arc A749 (13.0415, -5.3462) -> (13.0415, -3.6538) centre (12.3387, -4.5) ccw
  arc A750 (12.7349, -3.306) -> (13.0415, -3.6538) centre (14, -2.5) ccw
  arc A751 (12.7349, -3.306) -> (13.0415, -3.6538) centre (14, -2.5) ccw
  arc A752 (10.2618, 20.9233) -> (12.7349, -3.306) centre (35.6147, 11.2703) ccw
  arc A753 (10.2618, 20.9233) -> (12.7349, -3.306) centre (35.6147, 11.2703) ccw
  arc A754 (14, 23.5) -> (10.2618, 20.9233) centre (14, 19.5) ccw
  arc A755 (14, 23.5) -> (10.2618, 20.9233) centre (14, 19.5) ccw
  arc A756 (46.1132, 22.8962) -> (44, 23.5) centre (44, 19.5) ccw
  arc A757 (46.1132, 22.8962) -> (44, 23.5) centre (44, 19.5) ccw
  arc A758 (53, 10.5) -> (46.1132, 22.8962) centre (38.4, 10.5) ccw
  arc A759 (53, 10.5) -> (46.1132, 22.8962) centre (38.4, 10.5) ccw
  arc A760 (45.0112, -7.6079) -> (53, 10.5) centre (28.4833, 10.5) ccw
  arc A761 (45.0112, -7.6079) -> (53, 10.5) centre (28.4833, 10.5) ccw
  arc A762 (44.9585, -7.6538) -> (45.0112, -7.6079) centre (44, -6.5) ccw
  arc A763 (44.9585, -7.6538) -> (45.0112, -7.6079) centre (44, -6.5) ccw
  arc A764 (44.9585, -7.6538) -> (44.9585, -9.3462) centre (45.6613, -8.5) ccw
  arc A765 (44.9585, -7.6538) -> (44.9585, -9.3462) centre (45.6613, -8.5) ccw
  arc A766 (45.3238, -11.2053) -> (46.0883, -12.803) centre (46.2946, -11.7225) ccw
  arc A767 (45.3238, -11.2053) -> (46.0883, -12.803) centre (46.2946, -11.7225) ccw
  arc A768 (50.8, -18.5) -> (46.0883, -12.803) centre (45, -18.5) ccw
  arc A769 (50.8, -18.5) -> (46.0883, -12.803) centre (45, -18.5) ccw
  arc A770 (44, -25.8) -> (50.8, -19) centre (44, -19) ccw
  arc A771 (44, -25.8) -> (50.8, -19) centre (44, -19) ccw
  arc A772 (-28.2253, -19.072) -> (-22.5, -25.8) centre (-22.5, -20) ccw
  arc A773 (-28.2253, -19.072) -> (-22.5, -25.8) centre (-22.5, -20) ccw
  arc A774 (-28.2253, -19.072) -> (-30.3969, -16.52) centre (-30.3969, -18.72) ccw
  arc A775 (-28.2253, -19.072) -> (-30.3969, -16.52) centre (-30.3969, -18.72) ccw
  arc A780 (35.0859, -3.5349) -> (35.1134, -1.4948) centre (34, -2.5) ccw
  arc A781 (35.0859, -3.5349) -> (35.1134, -1.4948) centre (34, -2.5) ccw
  arc A782 (35.7499, -6.9216) -> (35.1682, -5.1306) centre (34, -6.5) ccw
  arc A783 (35.7499, -6.9216) -> (35.1682, -5.1306) centre (34, -6.5) ccw
  arc A784 (35.7499, -6.9216) -> (37.1098, -7.6577) centre (36.5277, -7.1089) ccw
  arc A785 (35.7499, -6.9216) -> (37.1098, -7.6577) centre (36.5277, -7.1089) ccw
  arc A786 (32.5011, 19.4423) -> (31.4019, 20.5) centre (31.4019, 19.4) ccw
  arc A787 (32.5011, 19.4423) -> (31.4019, 20.5) centre (31.4019, 19.4) ccw
  arc A788 (20.5, 10.5) -> (17.336, 18.6583) centre (8.4, 10.5) ccw
  arc A789 (20.5, 10.5) -> (17.336, 18.6583) centre (8.4, 10.5) ccw
  arc A790 (20.5, 10.5) -> (25.1134, -1.4948) centre (38.4, 10.5) ccw
  arc A791 (20.5, 10.5) -> (25.1134, -1.4948) centre (38.4, 10.5) ccw
  arc A792 (24.9585, -3.6538) -> (25.1134, -1.4948) centre (24, -2.5) ccw
  arc A793 (24.9585, -3.6538) -> (25.1134, -1.4948) centre (24, -2.5) ccw
  arc A794 (24.9585, -3.6538) -> (24.9585, -5.3462) centre (25.6613, -4.5) ccw
  arc A795 (24.9585, -3.6538) -> (24.9585, -5.3462) centre (25.6613, -4.5) ccw
  arc A796 (25.0859, -7.5349) -> (24.9585, -5.3462) centre (24, -6.5) ccw
  arc A797 (25.0859, -7.5349) -> (24.9585, -5.3462) centre (24, -6.5) ccw
  arc A798 (25.0859, -7.5349) -> (25.1682, -9.1306) centre (25.8821, -8.2938) ccw
  arc A799 (25.0859, -7.5349) -> (25.1682, -9.1306) centre (25.8821, -8.2938) ccw
  arc A800 (24, -12.3) -> (25.1682, -9.1306) centre (24, -10.5) ccw
  arc A801 (24, -12.3) -> (25.1682, -9.1306) centre (24, -10.5) ccw
  arc A802 (24, -12.3) -> (20.7586, -13.5966) centre (24, -17) ccw
  arc A804 (24, -12.3) -> (20.7586, -13.5966) centre (24, -17) ccw
  arc A806 (6.3795, -12.6618) -> (20.7586, -13.5966) centre (14, -6.5) ccw
  arc A807 (6.3795, -12.6618) -> (20.7586, -13.5966) centre (14, -6.5) ccw
  arc A808 (6.3795, -12.6618) -> (-2.2958, -8.52) centre (-2.2958, -19.6763) ccw
  arc A809 (6.3795, -12.6618) -> (-2.2958, -8.52) centre (-2.2958, -19.6763) ccw
  arc A810 (-48.9, -8.52) -> (-48.9, -12.92) centre (-48.9, -10.72) ccw
  arc A811 (-48.9, -8.52) -> (-48.9, -12.92) centre (-48.9, -10.72) ccw
  arc A812 (-24.6717, -19.648) -> (-30.3969, -12.92) centre (-30.3969, -18.72) ccw
  arc A813 (-24.6717, -19.648) -> (-30.3969, -12.92) centre (-30.3969, -18.72) ccw
  arc A814 (-24.6717, -19.648) -> (-22.5, -22.2) centre (-22.5, -20) ccw
  arc A815 (-24.6717, -19.648) -> (-22.5, -22.2) centre (-22.5, -20) ccw
  arc A816 (44, -22.2) -> (47.2, -19) centre (44, -19) ccw
  arc A817 (44, -22.2) -> (47.2, -19) centre (44, -19) ccw
  arc A818 (47.2, -18.5) -> (45, -16.3) centre (45, -18.5) ccw
  arc A819 (47.2, -18.5) -> (45, -16.3) centre (45, -18.5) ccw
  arc A820 (32.1636, -4.9984) -> (34, -16.3) centre (34, -10.5) ccw
  arc A821 (32.1636, -4.9984) -> (34, -16.3) centre (34, -10.5) ccw
  arc A822 (32.1636, -4.9984) -> (32.6445, -3.2323) centre (31.8153, -3.955) ccw
  arc A823 (32.1636, -4.9984) -> (32.6445, -3.2323) centre (31.8153, -3.955) ccw
  arc A824 (22.5011, 19.4423) -> (21.4019, 20.5) centre (21.4019, 19.4) ccw
  arc A825 (22.5011, 19.4423) -> (21.4019, 20.5) centre (21.4019, 19.4) ccw
  arc A826 (18.1483, 20.5) -> (17.336, 18.6583) centre (18.1483, 19.4) ccw
  arc A827 (18.1483, 20.5) -> (17.336, 18.6583) centre (18.1483, 19.4) ccw
  arc A828 (28.1483, 20.5) -> (27.336, 18.6583) centre (28.1483, 19.4) ccw
  arc A829 (28.1483, 20.5) -> (27.336, 18.6583) centre (28.1483, 19.4) ccw
  arc A830 (35.0859, -3.5349) -> (35.1682, -5.1306) centre (35.8821, -4.2937) ccw
  arc A831 (35.0859, -3.5349) -> (35.1682, -5.1306) centre (35.8821, -4.2937) ccw
  arc A832 (17.5, 10.5) -> (22.5991, -3.18) centre (38.4, 10.5) ccw
  arc A833 (40.5, -6.8028) -> (40.7681, -7.5225) centre (41.6, -6.8028) ccw
  arc A834 (40.5, -6.8028) -> (40.7681, -7.5225) centre (41.6, -6.8028) ccw
  arc A835 (41.0911, -7.8571) -> (42.5648, -6.9361) centre (41.7037, -7.1978) ccw
  arc A836 (41.0911, -7.8571) -> (42.5648, -6.9361) centre (41.7037, -7.1978) ccw
  arc A837 (42.9888, -5.3921) -> (42.5648, -6.9361) centre (44, -6.5) ccw
  arc A838 (42.9888, -5.3921) -> (42.5648, -6.9361) centre (44, -6.5) ccw
  arc A839 (42.9888, -5.3921) -> (43.0826, -5.306) centre (28.4833, 10.5) ccw
  arc A840 (42.9888, -5.3921) -> (43.0826, -5.306) centre (28.4833, 10.5) ccw
  arc A841 (43.0826, -5.306) -> (43.0401, -3.6527) centre (42.3362, -4.4979) ccw
  arc A842 (43.0826, -5.306) -> (43.0401, -3.6527) centre (42.3362, -4.4979) ccw
  arc A843 (42.5011, 19.4423) -> (41.4019, 20.5) centre (41.4019, 19.4) ccw
  arc A844 (42.5011, 19.4423) -> (41.4019, 20.5) centre (41.4019, 19.4) ccw
  arc A845 (38.1483, 20.5) -> (37.336, 18.6583) centre (38.1483, 19.4) ccw
  arc A846 (38.1483, 20.5) -> (37.336, 18.6583) centre (38.1483, 19.4) ccw
  arc A847 (17.5, 10.5) -> (13.9413, 17.7183) centre (8.4, 10.5) ccw
  arc A848 (13.9413, 17.7183) -> (12.2042, 17.1121) centre (13.2714, 16.8458) ccw
  arc A849 (12.2042, 17.1121) -> (15.2651, -1.694) centre (35.6147, 11.2703) ccw
  arc A850 (-44.164, -3.1822) -> (-43.8352, -4.92) centre (-43.8352, -4.02) ccw
  arc A851 (-23.8252, -4.92) -> (-23.3471, -3.2575) centre (-23.8252, -4.02) ccw
  arc A852 (-24.9383, -1.8323) -> (-23.3471, -3.2575) centre (-20.0003, 2.08) ccw
  arc A853 (-29.447, 5.5336) -> (-29.3757, 3.7685) centre (-28.2, 4.7) ccw
  arc A854 (-29.447, 5.5336) -> (-30.8069, 9.8717) centre (-31.873, 7.1554) ccw
  arc A855 (-32.7947, 10.6519) -> (-36.5869, 9.6293) centre (-34.0003, 7.58) ccw
  arc A856 (-41.0596, 3.9856) -> (-41.0243, 4.0285) centre (-42.2, 4.96) ccw
  arc A857 (-41.0596, 3.9856) -> (-41.0596, 0.1744) centre (-38.8294, 2.08) ccw
  arc A858 (-41.652, -2.1963) -> (-41.0596, 0.1744) centre (-42.2, -0.8) ccw
  arc A860 (-23.8252, -4.92) -> (-23.3471, -3.2575) centre (-23.8252, -4.02) ccw
  arc A861 (-24.9383, -1.8323) -> (-23.3471, -3.2575) centre (-20.0003, 2.08) ccw
  arc A862 (-29.447, 5.5336) -> (-29.3757, 3.7685) centre (-28.2, 4.7) ccw
  arc A863 (-29.447, 5.5336) -> (-30.8069, 9.8717) centre (-31.873, 7.1554) ccw
  arc A864 (-32.7947, 10.6519) -> (-36.5869, 9.6293) centre (-34.0003, 7.58) ccw
  arc A865 (-41.0596, 3.9856) -> (-41.0243, 4.0285) centre (-42.2, 4.96) ccw
  arc A866 (-41.0596, 3.9856) -> (-41.0596, 0.1744) centre (-38.8294, 2.08) ccw
  arc A867 (-41.652, -2.1963) -> (-41.0596, 0.1744) centre (-42.2, -0.8) ccw
  arc A868 (15.264, -3.3077) -> (15.2651, -1.694) centre (14, -2.5) ccw
  arc A869 (15.4816, -10.7344) -> (15.264, -9.6923) centre (14, -10.5) ccw
  arc A870 (19.502, -10.0245) -> (18.2759, -10.9897) centre (24, -17) ccw
  arc A871 (19.502, -10.0245) -> (18.9059, -8) centre (18.9059, -9.1) ccw
  arc A872 (19.502, -10.0245) -> (18.9059, -8) centre (18.9059, -9.1) ccw
  arc A873 (16.1909, -8) -> (15.264, -9.6923) centre (16.1909, -9.1) ccw
  arc A874 (15.4816, -10.7344) -> (15.264, -9.6923) centre (14, -10.5) ccw
  arc A878 (16.1909, -8) -> (15.264, -9.6923) centre (16.1909, -9.1) ccw
  arc A879 (15.264, -3.3077) -> (16.1909, -5) centre (16.1909, -3.9) ccw
  arc A880 (21.7675, -5) -> (22.5991, -3.18) centre (21.7675, -3.9) ccw
  arc A881 (17.5, 10.5) -> (22.5991, -3.18) centre (38.4, 10.5) ccw
  arc A882 (17.5, 10.5) -> (13.9413, 17.7183) centre (8.4, 10.5) ccw
  arc A883 (13.9413, 17.7183) -> (12.2042, 17.1121) centre (13.2714, 16.8458) ccw
  arc A884 (12.2042, 17.1121) -> (15.2651, -1.694) centre (35.6147, 11.2703) ccw
  arc A885 (15.4816, -10.7344) -> (17.122, -11.8566) centre (16.5681, -10.9063) ccw
  arc A886 (15.4816, -10.7344) -> (17.122, -11.8566) centre (16.5681, -10.9063) ccw
  arc A887 (-16.164, -3.1822) -> (-15.8352, -4.92) centre (-15.8352, -4.02) ccw
  arc A888 (-44.164, -3.1822) -> (-43.8352, -4.92) centre (-43.8352, -4.02) ccw
  arc A889 (17.122, -11.8566) -> (18.2759, -10.9897) centre (14, -6.5) ccw
  arc A890 (17.122, -11.8566) -> (18.2759, -10.9897) centre (14, -6.5) ccw
  dimension "D1" = 0.6
  dimension "D2" = 0.6
  dimension "D3" = 0.6
  dimension "D4" = 0.6
  dimension "D5" = 0.6
  dimension "D6" = 0.6
  dimension "D7" = 0.6
  dimension "D8" = 0.6
  dimension "D9" = 0.6
  dimension "D10" = 0.6
  dimension "D11" = 0.35
  dimension "D12" = 0.35
  dimension "D13" = 0.35
  dimension "D14" = 0.35
  dimension "D15" = 0.35
  dimension "D16" = 0.35
  dimension "D17" = 0.35
  dimension "D18" = 0.35
  dimension "D19" = 0.35
  dimension "D20" = 0.35
  dimension "D21" = 0.35
  dimension "D22" = 0.35
extrude "Boss-Extrude1" add sketch "Sketch25" along normal blind 0.79 separate body contours A775 A773 L321 A771 L319 A769 A767 A35 A765 A763 A761 A759 A757 L317 A755 A753 A751 A749 A739 A747 L315 A745 A737 A735 L313 A733 L311 A731 A729 L309 A727 L307 A725 A723 A721 L305 A719 L303 A717 A715 L301 A713 L299 A711 L297 A709 A743 A741 L323 A884
delete or keep bodies "Body-Delete/Keep 1" type delete bodies bodies 101
sketch "0.1 offset" plane through (0, 0, 0) normal (0, 1, 0) x (1, 0, 0)
  line L26 (21.4019, 20.4) -> (18.1483, 20.4)
  line L27 (45, -16.4) -> (34, -16.4)
  line L28 (-22.5, -25.9) -> (44, -25.9)
  line L32 (50.9, -19) -> (50.9, -18.5)
  line L33 (44, 23.6) -> (14, 23.6)
  line L34 (10.7562, -6.3054) -> (1.0442, 5.706)
  line L35 (0.3845, 11.9494) -> (-3.6621, 13.5376)
  line L36 (-11.0167, 11.5544) -> (-15.4541, 5.9536)
  line L37 (-16.8611, -0.1256) -> (-18.8312, -0.8988)
  line L38 (-22.5085, 0.0928) -> (-26.9459, 5.6936)
  line L39 (-27.6155, 11.9494) -> (-31.6621, 13.5376)
  line L40 (-39.0167, 11.5544) -> (-43.4541, 5.9536)
  line L41 (-44.8611, -0.1256) -> (-46.8312, -0.8988)
  line L42 (-51.1779, 2.458) -> (-49.4112, 17.311)
  line L43 (-52.5888, 17.689) -> (-54.3555, 2.8359)
  line L44 (-48.9, -16.62) -> (-30.3969, -16.62)
  line L45 (-22.5, -25.9) -> (44, -25.9)
  line L46 (50.9, -19) -> (50.9, -18.5)
  line L47 (44, 23.6) -> (14, 23.6)
  line L64 (10.7562, -6.3054) -> (1.0442, 5.706)
  line L65 (0.3845, 11.9494) -> (-3.6621, 13.5376)
  line L66 (-11.0167, 11.5544) -> (-15.4541, 5.9536)
  line L67 (-16.8611, -0.1256) -> (-18.8312, -0.8988)
  line L68 (-22.5085, 0.0928) -> (-26.9459, 5.6936)
  line L69 (-27.6155, 11.9494) -> (-31.6621, 13.5376)
  line L70 (-39.0167, 11.5544) -> (-43.4541, 5.9536)
  line L71 (-44.8611, -0.1256) -> (-46.8312, -0.8988)
  line L72 (-51.1779, 2.458) -> (-49.4112, 17.311)
  line L73 (-52.5888, 17.689) -> (-54.3555, 2.8359)
  line L74 (-48.9, -16.62) -> (-30.3969, -16.62)
  line L77 (47.1, -19) -> (47.1, -18.5)
  line L78 (-22.5, -22.1) -> (44, -22.1)
  line L79 (-48.9, -12.82) -> (-30.3969, -12.82)
  line L80 (-2.2958, -8.62) -> (-48.9, -8.62)
  line L81 (21.4019, 20.4) -> (18.1483, 20.4)
  line L82 (45, -16.4) -> (34, -16.4)
  line L83 (47.1, -19) -> (47.1, -18.5)
  line L84 (-22.5, -22.1) -> (44, -22.1)
  line L85 (-48.9, -12.82) -> (-30.3969, -12.82)
  line L86 (-2.2958, -8.62) -> (-48.9, -8.62)
  line L91 (-41.6155, -2.2894) -> (-44.1275, -3.2753)
  line L92 (-36.5085, 9.5672) -> (-40.9459, 3.9664)
  line L93 (-30.8434, 9.7786) -> (-32.8312, 10.5588)
  line L94 (-25.0167, -1.8944) -> (-29.4541, 3.7064)
  line L95 (-43.8352, -4.82) -> (-23.8252, -4.82)
  line L96 (-41.6155, -2.2894) -> (-44.1275, -3.2753)
  line L97 (-36.5085, 9.5672) -> (-40.9459, 3.9664)
  line L98 (-30.8434, 9.7786) -> (-32.8312, 10.5588)
  line L99 (-25.0167, -1.8944) -> (-29.4541, 3.7064)
  line L100 (-43.8352, -4.82) -> (-23.8252, -4.82)
  line L103 (18.9059, -8.1) -> (16.1909, -8.1)
  line L104 (18.9059, -8.1) -> (16.1909, -8.1)
  line L106 (5.4127, -4.7862) -> (-1.4442, 3.694)
  line L107 (-15.8352, -4.82) -> (-2.2958, -4.82)
  line L108 (-13.6155, -2.2894) -> (-16.1275, -3.2753)
  line L109 (-8.5085, 9.5672) -> (-12.9459, 3.9664)
  line L110 (-2.8434, 9.7786) -> (-4.8312, 10.5588)
  line L111 (5.4127, -4.7862) -> (-1.4442, 3.694)
  line L112 (-15.8352, -4.82) -> (-2.2958, -4.82)
  line L113 (-13.6155, -2.2894) -> (-16.1275, -3.2753)
  line L114 (-8.5085, 9.5672) -> (-12.9459, 3.9664)
  line L115 (-2.8434, 9.7786) -> (-4.8312, 10.5588)
  line L116 (16.1909, -4.9) -> (21.7675, -4.9)
  line L117 (16.1909, -4.9) -> (21.7675, -4.9)
  line L119 (38.0953, -12.6) -> (39.9047, -12.6)
  line L120 (38.0953, -12.6) -> (39.9047, -12.6)
  line L124 (31.4019, 20.4) -> (28.1483, 20.4)
  line L125 (37.4, -6.8028) -> (37.4, 10.5)
  line L126 (31.4019, 20.4) -> (28.1483, 20.4)
  line L127 (37.4, -6.8028) -> (37.4, 10.5)
  line L130 (41.4019, 20.4) -> (38.1483, 20.4)
  line L131 (40.6, 10.5) -> (40.6, -6.8028)
  line L132 (41.4019, 20.4) -> (38.1483, 20.4)
  line L133 (40.6, 10.5) -> (40.6, -6.8028)
  arc A70 (-28.324, -19.056) -> (-30.3969, -16.62) centre (-30.3969, -18.72) ccw
  arc A71 (-28.324, -19.056) -> (-22.5, -25.9) centre (-22.5, -20) ccw
  arc A72 (44, -25.9) -> (50.9, -19) centre (44, -19) ccw
  arc A73 (50.9, -18.5) -> (46.107, -12.7048) centre (45, -18.5) ccw
  arc A74 (45.4121, -11.2523) -> (46.107, -12.7048) centre (46.2946, -11.7225) ccw
  arc A75 (45.4121, -11.2523) -> (45.0224, -9.2692) centre (44, -10.5) ccw
  arc A76 (45.0224, -7.7308) -> (45.0224, -9.2692) centre (45.6613, -8.5) ccw
  arc A77 (45.0224, -7.7308) -> (45.0786, -7.6818) centre (44, -6.5) ccw
  arc A78 (45.0786, -7.6818) -> (53.1, 10.5) centre (28.4833, 10.5) ccw
  arc A79 (53.1, 10.5) -> (46.166, 22.9811) centre (38.4, 10.5) ccw
  arc A80 (46.166, 22.9811) -> (44, 23.6) centre (44, 19.5) ccw
  arc A81 (14, 23.6) -> (10.1683, 20.9589) centre (14, 19.5) ccw
  arc A82 (10.1683, 20.9589) -> (12.6506, -3.3597) centre (35.6147, 11.2703) ccw
  arc A83 (12.6506, -3.3597) -> (12.9776, -3.7308) centre (14, -2.5) ccw
  arc A84 (12.9776, -5.2692) -> (12.9776, -3.7308) centre (12.3387, -4.5) ccw
  arc A85 (12.9776, -5.2692) -> (12.4824, -5.9933) centre (14, -6.5) ccw
  arc A86 (10.7562, -6.3054) -> (12.4824, -5.9933) centre (11.5338, -5.6766) ccw
  arc A87 (1.0442, 5.706) -> (1.0133, 5.743) centre (-0.2, 4.7) ccw
  arc A88 (1.0133, 9.417) -> (1.0133, 5.743) centre (3.1504, 7.58) ccw
  arc A89 (1.0133, 9.417) -> (0.3845, 11.9494) centre (-0.2, 10.46) ccw
  arc A90 (-3.6621, 13.5376) -> (-11.0167, 11.5544) centre (-6.0003, 7.58) ccw
  arc A91 (-15.4541, 5.9536) -> (-15.534, 4.0765) centre (-14.2, 4.96) ccw
  arc A92 (-16.8611, -0.1256) -> (-15.534, 4.0765) centre (-17.8963, 2.512) ccw
  arc A93 (-22.5085, 0.0928) -> (-18.8312, -0.8988) centre (-20.0003, 2.08) ccw
  arc A94 (-26.9459, 5.6936) -> (-26.9867, 5.743) centre (-28.2, 4.7) ccw
  arc A95 (-26.9867, 9.417) -> (-26.9867, 5.743) centre (-24.8496, 7.58) ccw
  arc A96 (-26.9867, 9.417) -> (-27.6155, 11.9494) centre (-28.2, 10.46) ccw
  arc A97 (-31.6621, 13.5376) -> (-39.0167, 11.5544) centre (-34.0003, 7.58) ccw
  arc A98 (-43.4541, 5.9536) -> (-43.534, 4.0765) centre (-42.2, 4.96) ccw
  arc A99 (-44.8611, -0.1256) -> (-43.534, 4.0765) centre (-45.8963, 2.512) ccw
  arc A100 (-51.1779, 2.458) -> (-46.8312, -0.8988) centre (-48.0003, 2.08) ccw
  arc A101 (-49.4112, 17.311) -> (-52.5888, 17.689) centre (-51, 17.5) ccw
  arc A136 (-54.3555, 2.8359) -> (-50.7846, -3.6826) centre (-48.0003, 2.08) ccw
  arc A137 (-50.8661, -5.1572) -> (-50.7846, -3.6826) centre (-51.1326, -4.4029) ccw
  arc A138 (-50.8661, -5.1572) -> (-48.9, -16.62) centre (-48.9, -10.72) ccw
  arc A139 (-28.324, -19.056) -> (-30.3969, -16.62) centre (-30.3969, -18.72) ccw
  arc A140 (-28.324, -19.056) -> (-22.5, -25.9) centre (-22.5, -20) ccw
  arc A141 (44, -25.9) -> (50.9, -19) centre (44, -19) ccw
  arc A142 (50.9, -18.5) -> (46.107, -12.7048) centre (45, -18.5) ccw
  arc A143 (45.4121, -11.2523) -> (46.107, -12.7048) centre (46.2946, -11.7225) ccw
  arc A144 (45.4121, -11.2523) -> (45.0224, -9.2692) centre (44, -10.5) ccw
  arc A145 (45.0224, -7.7308) -> (45.0224, -9.2692) centre (45.6613, -8.5) ccw
  arc A146 (45.0224, -7.7308) -> (45.0786, -7.6818) centre (44, -6.5) ccw
  arc A147 (45.0786, -7.6818) -> (53.1, 10.5) centre (28.4833, 10.5) ccw
  arc A148 (53.1, 10.5) -> (46.166, 22.9811) centre (38.4, 10.5) ccw
  arc A149 (46.166, 22.9811) -> (44, 23.6) centre (44, 19.5) ccw
  arc A150 (14, 23.6) -> (10.1683, 20.9589) centre (14, 19.5) ccw
  arc A151 (10.1683, 20.9589) -> (12.6506, -3.3597) centre (35.6147, 11.2703) ccw
  arc A152 (12.6506, -3.3597) -> (12.9776, -3.7308) centre (14, -2.5) ccw
  arc A153 (12.9776, -5.2692) -> (12.9776, -3.7308) centre (12.3387, -4.5) ccw
  arc A154 (12.9776, -5.2692) -> (12.4824, -5.9933) centre (14, -6.5) ccw
  arc A155 (10.7562, -6.3054) -> (12.4824, -5.9933) centre (11.5338, -5.6766) ccw
  arc A156 (1.0442, 5.706) -> (1.0133, 5.743) centre (-0.2, 4.7) ccw
  arc A157 (1.0133, 9.417) -> (1.0133, 5.743) centre (3.1504, 7.58) ccw
  arc A158 (1.0133, 9.417) -> (0.3845, 11.9494) centre (-0.2, 10.46) ccw
  arc A159 (-3.6621, 13.5376) -> (-11.0167, 11.5544) centre (-6.0003, 7.58) ccw
  arc A160 (-15.4541, 5.9536) -> (-15.534, 4.0765) centre (-14.2, 4.96) ccw
  arc A161 (-16.8611, -0.1256) -> (-15.534, 4.0765) centre (-17.8963, 2.512) ccw
  arc A162 (-22.5085, 0.0928) -> (-18.8312, -0.8988) centre (-20.0003, 2.08) ccw
  arc A163 (-26.9459, 5.6936) -> (-26.9867, 5.743) centre (-28.2, 4.7) ccw
  arc A164 (-26.9867, 9.417) -> (-26.9867, 5.743) centre (-24.8496, 7.58) ccw
  arc A165 (-26.9867, 9.417) -> (-27.6155, 11.9494) centre (-28.2, 10.46) ccw
  arc A166 (-31.6621, 13.5376) -> (-39.0167, 11.5544) centre (-34.0003, 7.58) ccw
  arc A167 (-43.4541, 5.9536) -> (-43.534, 4.0765) centre (-42.2, 4.96) ccw
  arc A168 (-44.8611, -0.1256) -> (-43.534, 4.0765) centre (-45.8963, 2.512) ccw
  arc A169 (-51.1779, 2.458) -> (-46.8312, -0.8988) centre (-48.0003, 2.08) ccw
  arc A170 (-49.4112, 17.311) -> (-52.5888, 17.689) centre (-51, 17.5) ccw
  arc A171 (-54.3555, 2.8359) -> (-50.7846, -3.6826) centre (-48.0003, 2.08) ccw
  arc A172 (-50.8661, -5.1572) -> (-50.7846, -3.6826) centre (-51.1326, -4.4029) ccw
  arc A173 (-50.8661, -5.1572) -> (-48.9, -16.62) centre (-48.9, -10.72) ccw
  arc A179 (-41.6155, -2.2894) -> (-40.9836, 0.2394) centre (-42.2, -0.8) ccw
  arc A180 (-40.9836, 3.9206) -> (-40.9836, 0.2394) centre (-38.8294, 2.08) ccw
  arc A181 (-40.9836, 3.9206) -> (-40.9459, 3.9664) centre (-42.2, 4.96) ccw
  arc A182 (-32.8312, 10.5588) -> (-36.5085, 9.5672) centre (-34.0003, 7.58) ccw
  arc A183 (18.1483, 20.4) -> (17.4098, 18.7258) centre (18.1483, 19.4) ccw
  arc A184 (22.4012, 19.4385) -> (21.4019, 20.4) centre (21.4019, 19.4) ccw
  arc A185 (22.4012, 19.4385) -> (23.1547, 18.1415) centre (24, 19.5) ccw
  arc A186 (27.4, 10.5) -> (23.1547, 18.1415) centre (18.4, 10.5) ccw
  arc A187 (27.4, 10.5) -> (32.5691, -3.298) centre (48.4, 10.5) ccw
  arc A188 (32.1319, -4.9036) -> (32.5691, -3.298) centre (31.8153, -3.955) ccw
  arc A189 (32.1319, -4.9036) -> (34, -16.4) centre (34, -10.5) ccw
  arc A190 (47.1, -18.5) -> (45, -16.4) centre (45, -18.5) ccw
  arc A191 (44, -22.1) -> (47.1, -19) centre (44, -19) ccw
  arc A192 (-24.5729, -19.664) -> (-22.5, -22.1) centre (-22.5, -20) ccw
  arc A193 (-24.5729, -19.664) -> (-30.3969, -12.82) centre (-30.3969, -18.72) ccw
  arc A194 (-48.9, -8.62) -> (-48.9, -12.82) centre (-48.9, -10.72) ccw
  arc A195 (6.3017, -12.7246) -> (-2.2958, -8.62) centre (-2.2958, -19.6763) ccw
  arc A208 (6.3017, -12.7246) -> (20.8276, -13.669) centre (14, -6.5) ccw
  arc A209 (24, -12.4) -> (20.8276, -13.669) centre (24, -17) ccw
  arc A210 (24, -12.4) -> (25.2331, -9.0545) centre (24, -10.5) ccw
  arc A211 (25.1582, -7.6038) -> (25.2331, -9.0545) centre (25.8821, -8.2938) ccw
  arc A212 (25.1582, -7.6038) -> (25.0224, -5.2692) centre (24, -6.5) ccw
  arc A213 (25.0224, -3.7308) -> (25.0224, -5.2692) centre (25.6613, -4.5) ccw
  arc A214 (25.0224, -3.7308) -> (25.1876, -1.4278) centre (24, -2.5) ccw
  arc A215 (20.6, 10.5) -> (25.1876, -1.4278) centre (38.4, 10.5) ccw
  arc A216 (20.6, 10.5) -> (17.4098, 18.7258) centre (8.4, 10.5) ccw
  arc A217 (18.1483, 20.4) -> (17.4098, 18.7258) centre (18.1483, 19.4) ccw
  arc A218 (22.4012, 19.4385) -> (21.4019, 20.4) centre (21.4019, 19.4) ccw
  arc A219 (22.4012, 19.4385) -> (23.1547, 18.1415) centre (24, 19.5) ccw
  arc A220 (27.4, 10.5) -> (23.1547, 18.1415) centre (18.4, 10.5) ccw
  arc A221 (27.4, 10.5) -> (32.5691, -3.298) centre (48.4, 10.5) ccw
  arc A222 (32.1319, -4.9036) -> (32.5691, -3.298) centre (31.8153, -3.955) ccw
  arc A223 (32.1319, -4.9036) -> (34, -16.4) centre (34, -10.5) ccw
  arc A224 (47.1, -18.5) -> (45, -16.4) centre (45, -18.5) ccw
  arc A225 (44, -22.1) -> (47.1, -19) centre (44, -19) ccw
  arc A226 (-24.5729, -19.664) -> (-22.5, -22.1) centre (-22.5, -20) ccw
  arc A227 (-24.5729, -19.664) -> (-30.3969, -12.82) centre (-30.3969, -18.72) ccw
  arc A228 (-48.9, -8.62) -> (-48.9, -12.82) centre (-48.9, -10.72) ccw
  arc A229 (6.3017, -12.7246) -> (-2.2958, -8.62) centre (-2.2958, -19.6763) ccw
  arc A230 (6.3017, -12.7246) -> (20.8276, -13.669) centre (14, -6.5) ccw
  arc A232 (24, -12.4) -> (25.2331, -9.0545) centre (24, -10.5) ccw
  arc A233 (25.1582, -7.6038) -> (25.2331, -9.0545) centre (25.8821, -8.2938) ccw
  arc A234 (25.1582, -7.6038) -> (25.0224, -5.2692) centre (24, -6.5) ccw
  arc A235 (25.0224, -3.7308) -> (25.0224, -5.2692) centre (25.6613, -4.5) ccw
  arc A236 (25.0224, -3.7308) -> (25.1876, -1.4278) centre (24, -2.5) ccw
  arc A237 (20.6, 10.5) -> (25.1876, -1.4278) centre (38.4, 10.5) ccw
  arc A238 (20.6, 10.5) -> (17.4098, 18.7258) centre (8.4, 10.5) ccw
  arc A239 (-29.5302, 5.5892) -> (-30.8434, 9.7786) centre (-31.873, 7.1554) ccw
  arc A240 (-29.5302, 5.5892) -> (-29.4541, 3.7064) centre (-28.2, 4.7) ccw
  arc A241 (-25.0167, -1.8944) -> (-23.4002, -3.3422) centre (-20.0003, 2.08) ccw
  arc A242 (-23.8252, -4.82) -> (-23.4002, -3.3422) centre (-23.8252, -4.02) ccw
  arc A243 (-44.1275, -3.2753) -> (-43.8352, -4.82) centre (-43.8352, -4.02) ccw
  arc A244 (-41.6155, -2.2894) -> (-40.9836, 0.2394) centre (-42.2, -0.8) ccw
  arc A245 (-40.9836, 3.9206) -> (-40.9836, 0.2394) centre (-38.8294, 2.08) ccw
  arc A246 (-40.9836, 3.9206) -> (-40.9459, 3.9664) centre (-42.2, 4.96) ccw
  arc A247 (-32.8312, 10.5588) -> (-36.5085, 9.5672) centre (-34.0003, 7.58) ccw
  arc A248 (-29.5302, 5.5892) -> (-30.8434, 9.7786) centre (-31.873, 7.1554) ccw
  arc A249 (-29.5302, 5.5892) -> (-29.4541, 3.7064) centre (-28.2, 4.7) ccw
  arc A250 (-25.0167, -1.8944) -> (-23.4002, -3.3422) centre (-20.0003, 2.08) ccw
  arc A251 (-23.8252, -4.82) -> (-23.4002, -3.3422) centre (-23.8252, -4.02) ccw
  arc A262 (-1.5302, 5.5892) -> (-2.8434, 9.7786) centre (-3.873, 7.1554) ccw
  arc A263 (-1.5302, 5.5892) -> (-1.4442, 3.694) centre (-0.2, 4.7) ccw
  arc A264 (4.198, -6.3144) -> (5.4127, -4.7862) centre (4.6351, -5.415) ccw
  arc A265 (4.198, -6.3144) -> (-2.2958, -4.82) centre (-2.2958, -19.6763) ccw
  arc A266 (-16.1275, -3.2753) -> (-15.8352, -4.82) centre (-15.8352, -4.02) ccw
  arc A267 (-13.6155, -2.2894) -> (-12.9836, 0.2394) centre (-14.2, -0.8) ccw
  arc A268 (-12.9836, 3.9206) -> (-12.9836, 0.2394) centre (-10.8294, 2.08) ccw
  arc A269 (-12.9836, 3.9206) -> (-12.9459, 3.9664) centre (-14.2, 4.96) ccw
  arc A270 (-4.8312, 10.5588) -> (-8.5085, 9.5672) centre (-6.0003, 7.58) ccw
  arc A271 (-1.5302, 5.5892) -> (-2.8434, 9.7786) centre (-3.873, 7.1554) ccw
  arc A272 (-1.5302, 5.5892) -> (-1.4442, 3.694) centre (-0.2, 4.7) ccw
  arc A273 (4.198, -6.3144) -> (5.4127, -4.7862) centre (4.6351, -5.415) ccw
  arc A274 (4.198, -6.3144) -> (-2.2958, -4.82) centre (-2.2958, -19.6763) ccw
  arc A276 (-13.6155, -2.2894) -> (-12.9836, 0.2394) centre (-14.2, -0.8) ccw
  arc A277 (-12.9836, 3.9206) -> (-12.9836, 0.2394) centre (-10.8294, 2.08) ccw
  arc A278 (-12.9836, 3.9206) -> (-12.9459, 3.9664) centre (-14.2, 4.96) ccw
  arc A279 (-4.8312, 10.5588) -> (-8.5085, 9.5672) centre (-6.0003, 7.58) ccw
  arc A281 (16.1909, -8.1) -> (15.3482, -9.6385) centre (16.1909, -9.1) ccw
  arc A282 (17.0716, -11.7702) -> (18.2069, -10.9172) centre (14, -6.5) ccw
  arc A283 (17.0716, -11.7702) -> (18.2069, -10.9172) centre (14, -6.5) ccw
  arc A284 (15.5803, -10.75) -> (17.0716, -11.7702) centre (16.5681, -10.9063) ccw
  arc A285 (15.5803, -10.75) -> (15.3482, -9.6385) centre (14, -10.5) ccw
  arc A286 (16.1909, -8.1) -> (15.3482, -9.6385) centre (16.1909, -9.1) ccw
  arc A290 (15.5803, -10.75) -> (15.3482, -9.6385) centre (14, -10.5) ccw
  arc A311 (12.3012, 17.0879) -> (15.3494, -1.6403) centre (35.6147, 11.2703) ccw
  arc A312 (13.8804, 17.639) -> (12.3012, 17.0879) centre (13.2714, 16.8458) ccw
  arc A313 (17.4, 10.5) -> (13.8804, 17.639) centre (8.4, 10.5) ccw
  arc A314 (17.4, 10.5) -> (22.5235, -3.2455) centre (38.4, 10.5) ccw
  arc A315 (21.7675, -4.9) -> (22.5235, -3.2455) centre (21.7675, -3.9) ccw
  arc A316 (15.3482, -3.3615) -> (16.1909, -4.9) centre (16.1909, -3.9) ccw
  arc A317 (15.3482, -3.3615) -> (15.3494, -1.6403) centre (14, -2.5) ccw
  arc A318 (12.3012, 17.0879) -> (15.3494, -1.6403) centre (35.6147, 11.2703) ccw
  arc A319 (13.8804, 17.639) -> (12.3012, 17.0879) centre (13.2714, 16.8458) ccw
  arc A320 (17.4, 10.5) -> (13.8804, 17.639) centre (8.4, 10.5) ccw
  arc A321 (17.4, 10.5) -> (22.5235, -3.2455) centre (38.4, 10.5) ccw
  arc A322 (21.7675, -4.9) -> (22.5235, -3.2455) centre (21.7675, -3.9) ccw
  arc A323 (15.3482, -3.3615) -> (16.1909, -4.9) centre (16.1909, -3.9) ccw
  arc A324 (15.3482, -3.3615) -> (15.3494, -1.6403) centre (14, -2.5) ccw
  arc A328 (37.6945, -11.1077) -> (38.0953, -12.6) centre (38.0953, -11.8) ccw
  arc A329 (37.6945, -11.1077) -> (38.4029, -10.6412) centre (34, -4.7265) ccw
  arc A330 (39.5971, -10.6412) -> (38.4029, -10.6412) centre (39, -11.4433) ccw
  arc A331 (39.5971, -10.6412) -> (40.3055, -11.1077) centre (44, -4.7265) ccw
  arc A332 (39.9047, -12.6) -> (40.3055, -11.1077) centre (39.9047, -11.8) ccw
  arc A333 (37.6945, -11.1077) -> (38.0953, -12.6) centre (38.0953, -11.8) ccw
  arc A334 (37.6945, -11.1077) -> (38.4029, -10.6412) centre (34, -4.7265) ccw
  arc A335 (39.5971, -10.6412) -> (38.4029, -10.6412) centre (39, -11.4433) ccw
  arc A336 (39.5971, -10.6412) -> (40.3055, -11.1077) centre (44, -4.7265) ccw
  arc A337 (39.9047, -12.6) -> (40.3055, -11.1077) centre (39.9047, -11.8) ccw
  arc A357 (35.1582, -3.6038) -> (35.2331, -5.0545) centre (35.8821, -4.2937) ccw
  arc A358 (35.1582, -3.6038) -> (35.1876, -1.4278) centre (34, -2.5) ccw
  arc A359 (30.6, 10.5) -> (35.1876, -1.4278) centre (48.4, 10.5) ccw
  arc A360 (30.6, 10.5) -> (27.4098, 18.7258) centre (18.4, 10.5) ccw
  arc A361 (28.1483, 20.4) -> (27.4098, 18.7258) centre (28.1483, 19.4) ccw
  arc A362 (32.4012, 19.4385) -> (31.4019, 20.4) centre (31.4019, 19.4) ccw
  arc A363 (32.4012, 19.4385) -> (33.1547, 18.1415) centre (34, 19.5) ccw
  arc A364 (37.4, 10.5) -> (33.1547, 18.1415) centre (28.4, 10.5) ccw
  arc A365 (37.1563, -7.4571) -> (37.4, -6.8028) centre (36.4, -6.8028) ccw
  arc A366 (37.0371, -7.5891) -> (37.1563, -7.4571) centre (34, -4.7265) ccw
  arc A367 (35.8472, -6.945) -> (37.0371, -7.5891) centre (36.5277, -7.1089) ccw
  arc A368 (35.8472, -6.945) -> (35.2331, -5.0545) centre (34, -6.5) ccw
  arc A369 (35.1582, -3.6038) -> (35.2331, -5.0545) centre (35.8821, -4.2937) ccw
  arc A370 (35.1582, -3.6038) -> (35.1876, -1.4278) centre (34, -2.5) ccw
  arc A371 (30.6, 10.5) -> (35.1876, -1.4278) centre (48.4, 10.5) ccw
  arc A372 (30.6, 10.5) -> (27.4098, 18.7258) centre (18.4, 10.5) ccw
  arc A373 (28.1483, 20.4) -> (27.4098, 18.7258) centre (28.1483, 19.4) ccw
  arc A374 (32.4012, 19.4385) -> (31.4019, 20.4) centre (31.4019, 19.4) ccw
  arc A375 (32.4012, 19.4385) -> (33.1547, 18.1415) centre (34, 19.5) ccw
  arc A376 (37.4, 10.5) -> (33.1547, 18.1415) centre (28.4, 10.5) ccw
  arc A377 (37.1563, -7.4571) -> (37.4, -6.8028) centre (36.4, -6.8028) ccw
  arc A378 (37.0371, -7.5891) -> (37.1563, -7.4571) centre (34, -4.7265) ccw
  arc A379 (35.8472, -6.945) -> (37.0371, -7.5891) centre (36.5277, -7.1089) ccw
  arc A380 (35.8472, -6.945) -> (35.2331, -5.0545) centre (34, -6.5) ccw
  arc A388 (15.5803, -10.75) -> (17.0716, -11.7702) centre (16.5681, -10.9063) ccw
  arc A389 (19.4478, -9.9404) -> (18.9059, -8.1) centre (18.9059, -9.1) ccw
  arc A390 (19.4478, -9.9404) -> (18.9059, -8.1) centre (18.9059, -9.1) ccw
  arc A391 (-44.1275, -3.2753) -> (-43.8352, -4.82) centre (-43.8352, -4.02) ccw
  arc A392 (-16.1275, -3.2753) -> (-15.8352, -4.82) centre (-15.8352, -4.02) ccw
  arc A393 (19.4478, -9.9404) -> (18.2069, -10.9172) centre (24, -17) ccw
  arc A394 (19.4478, -9.9404) -> (18.2069, -10.9172) centre (24, -17) ccw
  arc A395 (38.1483, 20.4) -> (37.4098, 18.7258) centre (38.1483, 19.4) ccw
  arc A396 (42.4012, 19.4385) -> (41.4019, 20.4) centre (41.4019, 19.4) ccw
  arc A397 (42.4012, 19.4385) -> (43.1547, 18.1415) centre (44, 19.5) ccw
  arc A398 (47.4, 10.5) -> (43.1547, 18.1415) centre (38.4, 10.5) ccw
  arc A399 (42.8124, -1.4278) -> (47.4, 10.5) centre (29.6, 10.5) ccw
  arc A400 (42.8124, -1.4278) -> (42.9761, -3.7295) centre (44, -2.5) ccw
  arc A401 (43.0147, -5.2325) -> (42.9761, -3.7295) centre (42.3362, -4.4979) ccw
  arc A402 (42.9214, -5.3182) -> (43.0147, -5.2325) centre (28.4833, 10.5) ccw
  arc A403 (42.9214, -5.3182) -> (42.4691, -6.9652) centre (44, -6.5) ccw
  arc A404 (41.1591, -7.7839) -> (42.4691, -6.9652) centre (41.7037, -7.1978) ccw
  arc A405 (40.8437, -7.4571) -> (41.1591, -7.7839) centre (44, -4.7265) ccw
  arc A406 (40.6, -6.8028) -> (40.8437, -7.4571) centre (41.6, -6.8028) ccw
  arc A407 (40.6, 10.5) -> (37.4098, 18.7258) centre (28.4, 10.5) ccw
  arc A408 (38.1483, 20.4) -> (37.4098, 18.7258) centre (38.1483, 19.4) ccw
  arc A409 (42.4012, 19.4385) -> (41.4019, 20.4) centre (41.4019, 19.4) ccw
  arc A410 (42.4012, 19.4385) -> (43.1547, 18.1415) centre (44, 19.5) ccw
  arc A411 (47.4, 10.5) -> (43.1547, 18.1415) centre (38.4, 10.5) ccw
  arc A412 (42.8124, -1.4278) -> (47.4, 10.5) centre (29.6, 10.5) ccw
  arc A413 (42.8124, -1.4278) -> (42.9761, -3.7295) centre (44, -2.5) ccw
  arc A414 (43.0147, -5.2325) -> (42.9761, -3.7295) centre (42.3362, -4.4979) ccw
  arc A415 (42.9214, -5.3182) -> (43.0147, -5.2325) centre (28.4833, 10.5) ccw
  arc A416 (42.9214, -5.3182) -> (42.4691, -6.9652) centre (44, -6.5) ccw
  arc A417 (41.1591, -7.7839) -> (42.4691, -6.9652) centre (41.7037, -7.1978) ccw
  arc A418 (40.8437, -7.4571) -> (41.1591, -7.7839) centre (44, -4.7265) ccw
  arc A419 (40.6, -6.8028) -> (40.8437, -7.4571) centre (41.6, -6.8028) ccw
  arc A420 (40.6, 10.5) -> (37.4098, 18.7258) centre (28.4, 10.5) ccw
  arc A430 (24, -12.4) -> (20.8276, -13.669) centre (24, -17) ccw
  dimension "D1" = 0.1
  dimension "D2" = 0.1
  dimension "D3" = 0.1
  dimension "D4" = 0.1
  dimension "D5" = 0.1
  dimension "D6" = 0.1
  dimension "D7" = 0.1
  dimension "D8" = 0.1
  dimension "D9" = 0.1
